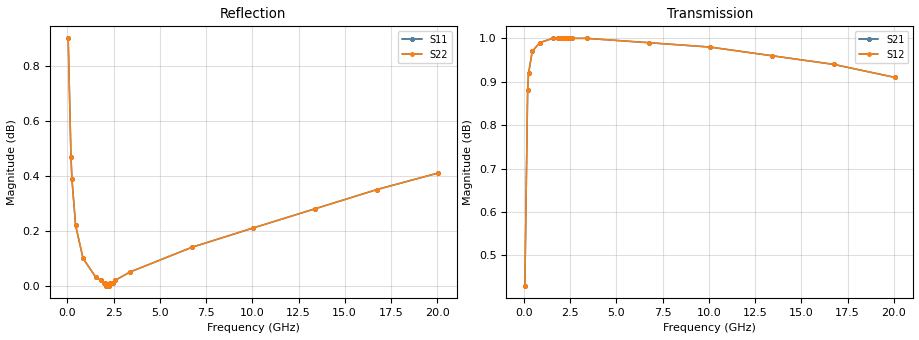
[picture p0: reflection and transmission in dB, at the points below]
! AVX Thin Film Operation		Date: may 2004
! Description: Accu-P® Series, Thin Film, SMD, RF Capacitor
! Part Number: 0201ZK150JBW
! 50 MHz  -  10.05 GHz
! Serial Measurements
# mhz S db R 50
!	S11		S21		S12		S22
!	dB	Phase	dB	Phase	dB	Phase	dB	Phase
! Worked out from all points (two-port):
!   401 points, 50 MHz to 20.05 GHz, reference 50 ohm
!   highest |S21| = 1.00 dB at 1.55 GHz (marker M1); lowest = 0.4 dB at 50 MHz (marker M2)
!   |S21| within 3 dB of the highest: start of sweep to end of sweep
!   lowest |S11| = 0.0 dB at 2.15 GHz (marker M3)
!   |S11| at or under -10 dB: nowhere
!   |S22| runs from 0.0 to 0.9 dB; largest |S21 - S12| = 0
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50  0.90 -25.2  0.43 64.7  0.43 64.7  0.90 -25.2
200  0.47 -62.1  0.88 27.7  0.88 27.7  0.47 -62.1
250  0.39 -67.1  0.92 22.7  0.92 22.7  0.39 -67.1
450  0.22 -76.9  0.97 12.7  0.97 12.7  0.22 -76.9
850  0.10 -83.1  0.99 6.0  0.99 6.0  0.10 -83.1
1550  0.03 -85.4  1.00 1.9  1.00 1.9  0.03 -85.4
1850  0.02 -83.4  1.00 0.9  1.00 0.9  0.02 -83.4
2000  0.01 -78.3  1.00 0.4  1.00 0.4  0.01 -78.3
2050  0.01 -73.6  1.00 0.3  1.00 0.3  0.01 -73.6
2100  0.00 -62.7  1.00 0.2  1.00 0.2  0.00 -62.7
2150  0.00 -24.8  1.00 0.0  1.00 0.0  0.00 -24.8
2250  0.00 67.3  1.00 -0.2  1.00 -0.2  0.00 67.3
2300  0.01 74.9  1.00 -0.3  1.00 -0.3  0.01 74.9
2350  0.01 78.6  1.00 -0.5  1.00 -0.5  0.01 78.6
2450  0.01 82.0  1.00 -0.7  1.00 -0.7  0.01 82.0
2600  0.02 84.0  1.00 -1.0  1.00 -1.0  0.02 84.0
3400  0.05 85.4  1.00 -2.6  1.00 -2.6  0.05 85.4
6750  0.14 81.6  0.99 -7.8  0.99 -7.8  0.14 81.6
10050  0.21 77.4  0.98 -12.2  0.98 -12.2  0.21 77.4
13400  0.28 73.3  0.96 -16.4  0.96 -16.4  0.28 73.3
16750  0.35 69.4  0.94 -20.4  0.94 -20.4  0.35 69.4
20050  0.41 65.7  0.91 -24.1  0.91 -24.1  0.41 65.7
